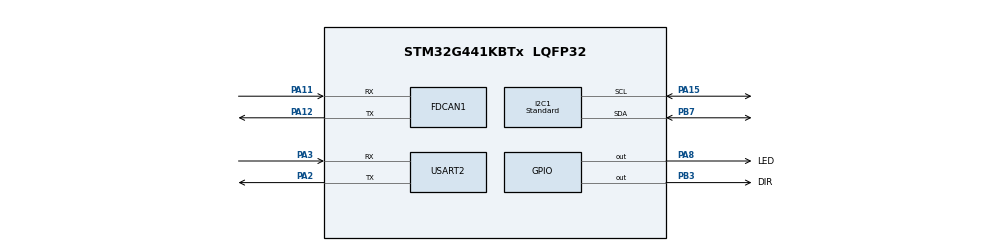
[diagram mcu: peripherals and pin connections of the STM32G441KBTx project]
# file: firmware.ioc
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FDCAN1.CalculateBaudRateNominal=500000
FDCAN1.CalculateTimeBitNominal=2000
FDCAN1.CalculateTimeQuantumNominal=125.0
FDCAN1.DataPrescaler=2
FDCAN1.DataSyncJumpWidth=4
FDCAN1.DataTimeSeg1=8
FDCAN1.DataTimeSeg2=3
FDCAN1.FrameFormat=FDCAN_FRAME_FD_BRS
FDCAN1.NominalPrescaler=6
FDCAN1.NominalSyncJumpWidth=4
FDCAN1.NominalTimeSeg1=9
FDCAN1.NominalTimeSeg2=6
FDCAN1.ProtocolException=ENABLE
FDCAN1.StdFiltersNbr=1
FREERTOS.Tasks01=defaultTask,24,128,StartDefaultTask,Default,NULL,Dynamic,NULL,NULL
FREERTOS.Timers01=as5600,as5600_timer_callback,osTimerPeriodic,Default,NULL,Dynamic,NULL
FREERTOS.configENABLE_FPU=1
FREERTOS.configTOTAL_HEAP_SIZE=8192
FREERTOS.configUSE_NEWLIB_REENTRANT=1
FREERTOS.configUSE_TIMERS=1
I2C1.CustomTiming=Enabled
I2C1.I2C_Speed_Mode=I2C_Standard
I2C1.Timing=0x300617
Mcu.Family=STM32G4
Mcu.Name=STM32G441KBTx
Mcu.Package=LQFP32
NVIC.FDCAN1_IT0_IRQn=true\:5\:0\:false\:false\:true\:true\:true\:true\:true
NVIC.I2C1_ER_IRQn=true\:5\:0\:false\:false\:true\:true\:true\:true\:true
NVIC.I2C1_EV_IRQn=true\:5\:0\:false\:false\:true\:true\:true\:true\:true
NVIC.PriorityGroup=NVIC_PRIORITYGROUP_4
NVIC.TIM8_UP_IRQn=true\:15\:0\:false\:false\:true\:false\:false\:true\:true
NVIC.TimeBase=TIM8_UP_IRQn
NVIC.TimeBaseIP=TIM8
PA11.Mode=FDCAN_Activate
PA11.Signal=FDCAN1_RX
PA12.Mode=FDCAN_Activate
PA12.Signal=FDCAN1_TX
PA13.Mode=Serial_Wire
PA13.Signal=SYS_JTMS-SWDIO
PA14.Mode=Serial_Wire
PA14.Signal=SYS_JTCK-SWCLK
PA15.GPIO_Pu=GPIO_PULLUP
PA15.GPIO_Speed=GPIO_SPEED_FREQ_VERY_HIGH
PA15.Mode=I2C
PA15.Signal=I2C1_SCL
PA2.Mode=Asynchronous
PA2.Signal=USART2_TX
PA3.Mode=Asynchronous
PA3.Signal=USART2_RX
PA8.GPIO_Label=LED
PA8.Signal=GPIO_Output
PB3.GPIO_Label=DIR
PB3.Signal=GPIO_Output
PB7.GPIO_Pu=GPIO_PULLUP
PB7.GPIO_Speed=GPIO_SPEED_FREQ_VERY_HIGH
PB7.Mode=I2C
PB7.Signal=I2C1_SDA
ProjectManager.HeapSize=0x200
ProjectManager.StackSize=0x400
ProjectManager.TargetToolchain=CMake
RCC.ADC12Freq_Value=96000000
RCC.AHBFreq_Value=96000000
RCC.APB1Freq_Value=96000000
RCC.APB1TimFreq_Value=96000000
RCC.APB2Freq_Value=96000000
RCC.APB2TimFreq_Value=96000000
RCC.CortexFreq_Value=96000000
RCC.EXTERNAL_CLOCK_VALUE=12288000
RCC.FDCANCLockSelection=RCC_FDCANCLKSOURCE_PLL
RCC.HCLKFreq_Value=96000000
RCC.HSE_VALUE=8000000
RCC.HSI48_VALUE=48000000
RCC.HSI_VALUE=16000000
RCC.I2C1CLockSelection=RCC_I2C1CLKSOURCE_HSI
RCC.LSE_VALUE=32768
RCC.PLLN=12
RCC.PLLQ=RCC_PLLQ_DIV4
RCC.SYSCLKFreq_VALUE=96000000
RCC.SYSCLKSource=RCC_SYSCLKSOURCE_PLLCLK
RCC.USART2CLockSelection=RCC_USART2CLKSOURCE_HSI
RCC.USBFreq_Value=48000000
RCC.VCOOutputFreq_Value=192000000
USART2.VirtualMode-Asynchronous=VM_ASYNC
VP_FREERTOS_VS_CMSIS_V2.Mode=CMSIS_V2
VP_SYS_VS_DBSignals.Mode=DisableDeadBatterySignals
VP_SYS_VS_tim8.Mode=TIM8
board=custom

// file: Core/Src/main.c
/* USER CODE BEGIN Header */
/**
 ******************************************************************************
 * @file           : main.c
 * @brief          : Main program body
 ******************************************************************************
 * @attention
 *
 * Copyright (c) 2025 STMicroelectronics.
 * All rights reserved.
 *
 * This software is licensed under terms that can be found in the LICENSE file
 * in the root directory of this software component.
 * If no LICENSE file comes with this software, it is provided AS-IS.
 *
 ******************************************************************************
 */
/* USER CODE END Header */
#include "main.h"
#include "cmsis_os.h"
#include "fdcan.h"
#include "i2c.h"
#include "usart.h"
#include "gpio.h"

/* USER CODE BEGIN Includes */
#include <stdio.h>
#include "SEGGER_RTT.h"
/* USER CODE END Includes */

void SystemClock_Config(void);
void MX_FREERTOS_Init(void);

/* USER CODE BEGIN 0 */

// FDCAN1 Callback
void HAL_FDCAN_RxFifo0Callback(FDCAN_HandleTypeDef *hfdcan, uint32_t RxFifo0ITs) {
	FDCAN_RxHeaderTypeDef	fdcan1RxHeader;
	uint8_t		fdcan1RxData[64];

	SEGGER_RTT_printf(0,"callback : ");

	if((RxFifo0ITs & FDCAN_IT_RX_FIFO0_NEW_MESSAGE) != RESET) {

		if (HAL_FDCAN_GetRxMessage(hfdcan, FDCAN_RX_FIFO0, &fdcan1RxHeader, fdcan1RxData) != HAL_OK) {
			/* Reception Error */
			Error_Handler();
		}

		SEGGER_RTT_printf(0,"fdcan1 received data from 0x%04x: ",fdcan1RxHeader.Identifier);
		// Prepare Tx data for fdcan2
		for (int32_t i = 0; i < 8; i++) {
			SEGGER_RTT_printf(0,"%02x, ", fdcan1RxData[i]);
		}
		SEGGER_RTT_printf(0," t=%d\n\r",HAL_GetTick());
		if (HAL_FDCAN_ActivateNotification(&hfdcan1, FDCAN_IT_RX_FIFO0_NEW_MESSAGE, 0) != HAL_OK) {
			Error_Handler();
		}
	}
}

/* USER CODE END 0 */

int main(void)
{

  /* USER CODE BEGIN 1 */
	setbuf(stdout, NULL);
  /* USER CODE END 1 */

  /* MCU Configuration--------------------------------------------------------*/

  /* Reset of all peripherals, Initializes the Flash interface and the Systick. */
  HAL_Init();

  /* USER CODE BEGIN Init */

	SEGGER_RTT_printf(0, "program started\n");

  /* USER CODE END Init */

  /* Configure the system clock */
  SystemClock_Config();

  /* Initialize all configured peripherals */
  MX_GPIO_Init();
  MX_FDCAN1_Init();
  MX_USART2_UART_Init();
  MX_I2C1_Init();
  /* USER CODE BEGIN 2 */

	if(HAL_FDCAN_Start(&hfdcan1)!= HAL_OK) {
		Error_Handler();
	}

	// Activate the notification for new data in FIFO0 for FDCAN1
	if (HAL_FDCAN_ActivateNotification(&hfdcan1, FDCAN_IT_RX_FIFO0_NEW_MESSAGE, 0) != HAL_OK) {
		Error_Handler();
	}

  /* USER CODE END 2 */

  /* Call init function for freertos objects (in cmsis_os2.c) */
  MX_FREERTOS_Init();

  /* Start scheduler */
  osKernelStart();

  /* We should never get here as control is now taken by the scheduler */

  /* Infinite loop */
	while (1)
	{

	}
}

void SystemClock_Config(void)
{
  RCC_OscInitTypeDef RCC_OscInitStruct = {0};
  RCC_ClkInitTypeDef RCC_ClkInitStruct = {0};

  /** Configure the main internal regulator output voltage
  */
  HAL_PWREx_ControlVoltageScaling(PWR_REGULATOR_VOLTAGE_SCALE1);

  /** Initializes the RCC Oscillators according to the specified parameters
  * in the RCC_OscInitTypeDef structure.
  */
  RCC_OscInitStruct.OscillatorType = RCC_OSCILLATORTYPE_HSI;
  RCC_OscInitStruct.HSIState = RCC_HSI_ON;
  RCC_OscInitStruct.HSICalibrationValue = RCC_HSICALIBRATION_DEFAULT;
  RCC_OscInitStruct.PLL.PLLState = RCC_PLL_ON;
  RCC_OscInitStruct.PLL.PLLSource = RCC_PLLSOURCE_HSI;
  RCC_OscInitStruct.PLL.PLLM = RCC_PLLM_DIV1;
  RCC_OscInitStruct.PLL.PLLN = 16;
  RCC_OscInitStruct.PLL.PLLP = RCC_PLLP_DIV2;
  RCC_OscInitStruct.PLL.PLLQ = RCC_PLLQ_DIV8;
  RCC_OscInitStruct.PLL.PLLR = RCC_PLLR_DIV2;
  if (HAL_RCC_OscConfig(&RCC_OscInitStruct) != HAL_OK)
  {
    Error_Handler();
  }

  /** Initializes the CPU, AHB and APB buses clocks
  */
  RCC_ClkInitStruct.ClockType = RCC_CLOCKTYPE_HCLK|RCC_CLOCKTYPE_SYSCLK
                              |RCC_CLOCKTYPE_PCLK1|RCC_CLOCKTYPE_PCLK2;
  RCC_ClkInitStruct.SYSCLKSource = RCC_SYSCLKSOURCE_PLLCLK;
  RCC_ClkInitStruct.AHBCLKDivider = RCC_SYSCLK_DIV1;
  RCC_ClkInitStruct.APB1CLKDivider = RCC_HCLK_DIV1;
  RCC_ClkInitStruct.APB2CLKDivider = RCC_HCLK_DIV1;

  if (HAL_RCC_ClockConfig(&RCC_ClkInitStruct, FLASH_LATENCY_4) != HAL_OK)
  {
    Error_Handler();
  }
}

/* USER CODE BEGIN 4 */
int _write(int file, char *ptr, int len)
{
	HAL_UART_Transmit(&huart2,(uint8_t *)ptr,len,10);
	return len;
}
/* USER CODE END 4 */

void HAL_TIM_PeriodElapsedCallback(TIM_HandleTypeDef *htim)
{
  if (htim->Instance == TIM8) {
    HAL_IncTick();
  }
}

void Error_Handler(void)
{
  /* USER CODE BEGIN Error_Handler_Debug */
	/* User can add his own implementation to report the HAL error return state */
	//__disable_irq();
	while (1)
	{
		HAL_GPIO_TogglePin(LED_GPIO_Port, LED_Pin);
		HAL_Delay(100);
	}
  /* USER CODE END Error_Handler_Debug */
}

#ifdef  USE_FULL_ASSERT
/**
  * @brief  Reports the name of the source file and the source line number
  *         where the assert_param error has occurred.
  * @param  file: pointer to the source file name
  * @param  line: assert_param error line source number
  * @retval None
  */
void assert_failed(uint8_t *file, uint32_t line)
{
  /* USER CODE BEGIN 6 */
	/* User can add his own implementation to report the file name and line number,
     ex: SEGGER_RTT_printf(0,"Wrong parameters value: file %s on line %d\r\n", file, line) */
  /* USER CODE END 6 */
}
#endif /* USE_FULL_ASSERT */

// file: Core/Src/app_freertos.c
/* USER CODE BEGIN Header */
/**
 ******************************************************************************
 * File Name          : app_freertos.c
 * Description        : Code for freertos applications
 ******************************************************************************
 * @attention
 *
 * Copyright (c) 2025 STMicroelectronics.
 * All rights reserved.
 *
 * This software is licensed under terms that can be found in the LICENSE file
 * in the root directory of this software component.
 * If no LICENSE file comes with this software, it is provided AS-IS.
 *
 ******************************************************************************
 */
/* USER CODE END Header */

#include "FreeRTOS.h"
#include "task.h"
#include "main.h"
#include "cmsis_os.h"

/* USER CODE BEGIN Includes */
#include "SEGGER_RTT.h"
#include "i2c.h"
#include "gpio.h"
#include "fdcan.h"
/* USER CODE END Includes */

TaskHandle_t defaultTaskHandle;
/* USER CODE BEGIN FunctionPrototypes */
int8_t user_i2c_read(uint8_t id, uint8_t reg_addr, uint8_t *data, uint16_t len);
/* USER CODE END FunctionPrototypes */

void StartDefaultTask(void *argument);

void MX_FREERTOS_Init(void); /* (MISRA C 2004 rule 8.1) */

void MX_FREERTOS_Init(void)
{

	/* Create the timer(s) */

	/* Create the thread(s) */
	/* definition and creation of defaultTask */

	xTaskCreate(StartDefaultTask, "defaultTask", 128, NULL, osPriorityNormal, &defaultTaskHandle);

}

void StartDefaultTask(void *argument)
{
	/* USER CODE BEGIN StartDefaultTask */
	UNUSED(argument);
	/* Infinite loop */
	SEGGER_RTT_printf(0, "defaultTask started\n");
	for (;;)
	{
		HAL_GPIO_WritePin(LED_GPIO_Port, LED_Pin, GPIO_PIN_RESET);
		uint8_t data[8];
		if (!user_i2c_read(0x36, 0x0C, data, 2)&&!user_i2c_read(0x36, 0x0B, data + 2, 1))
		{
			FDCAN_TxHeaderTypeDef TxHeader;
			TxHeader.Identifier = 0x442;
			TxHeader.IdType = FDCAN_STANDARD_ID;
			TxHeader.TxFrameType = FDCAN_DATA_FRAME;
			TxHeader.DataLength = FDCAN_DLC_BYTES_3;
			TxHeader.ErrorStateIndicator = FDCAN_ESI_ACTIVE;
			TxHeader.BitRateSwitch = FDCAN_BRS_OFF;
			TxHeader.FDFormat = FDCAN_CLASSIC_CAN;
			TxHeader.TxEventFifoControl = FDCAN_NO_TX_EVENTS;
			TxHeader.MessageMarker = 0;

			SEGGER_RTT_printf(0, "Angle: %d, Status: %02x\n", (data[0] << 8) | data[1], data[2]);

			if (HAL_FDCAN_AddMessageToTxFifoQ(&hfdcan1, &TxHeader, data) != HAL_OK)
			{
				Error_Handler();
			}
			HAL_GPIO_WritePin(LED_GPIO_Port, LED_Pin, GPIO_PIN_SET);
			while (HAL_FDCAN_GetTxFifoFreeLevel(&hfdcan1) != 3)
			{
			}
			HAL_GPIO_WritePin(LED_GPIO_Port, LED_Pin, GPIO_PIN_RESET);
		}
		else
		{
			SEGGER_RTT_printf(0, "error at user_i2c_read\n");
		}

		vTaskDelay(20);
	}
	/* USER CODE END StartDefaultTask */
}

/* USER CODE BEGIN Application */

int8_t user_i2c_read(uint8_t id, uint8_t reg_addr, uint8_t *data, uint16_t len)
{
	if (HAL_I2C_Master_Transmit(&hi2c1, (id << 1), &reg_addr, 1, 10) != HAL_OK)
		return -1;
	if (HAL_I2C_Master_Receive(&hi2c1, (id << 1) | 0x01, data, len, 10) != HAL_OK)
		return -1;

	return 0;
}

/* USER CODE END Application */
